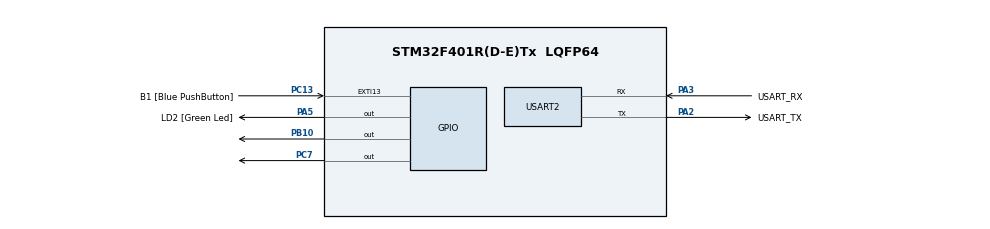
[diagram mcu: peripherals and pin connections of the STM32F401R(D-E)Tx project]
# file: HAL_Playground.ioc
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Mcu.Family=STM32F4
Mcu.Name=STM32F401R(D-E)Tx
Mcu.Package=LQFP64
NVIC.PriorityGroup=NVIC_PRIORITYGROUP_0
PA13.GPIO_Label=TMS
PA13.Mode=Serial_Wire
PA13.Signal=SYS_JTMS-SWDIO
PA14.GPIO_Label=TCK
PA14.Mode=Serial_Wire
PA14.Signal=SYS_JTCK-SWCLK
PA2.GPIO_Label=USART_TX
PA2.GPIO_Mode=GPIO_MODE_AF_PP
PA2.GPIO_PuPd=GPIO_NOPULL
PA2.GPIO_Speed=GPIO_SPEED_FREQ_LOW
PA2.Mode=Asynchronous
PA2.Signal=USART2_TX
PA3.GPIO_Label=USART_RX
PA3.GPIO_Mode=GPIO_MODE_AF_PP
PA3.GPIO_PuPd=GPIO_NOPULL
PA3.GPIO_Speed=GPIO_SPEED_FREQ_LOW
PA3.Mode=Asynchronous
PA3.Signal=USART2_RX
PA5.GPIO_Label=LD2 [Green Led]
PA5.GPIO_Mode=GPIO_MODE_OUTPUT_PP
PA5.GPIO_PuPd=GPIO_NOPULL
PA5.GPIO_Speed=GPIO_SPEED_FREQ_LOW
PA5.Signal=GPIO_Output
PB10.Signal=GPIO_Output
PB3.GPIO_Label=SWO
PB3.Signal=SYS_JTDO-SWO
PC13-ANTI_TAMP.GPIO_Label=B1 [Blue PushButton]
PC13-ANTI_TAMP.GPIO_ModeDefaultEXTI=GPIO_MODE_IT_FALLING
PC13-ANTI_TAMP.GPIO_PuPd=GPIO_NOPULL
PC13-ANTI_TAMP.Signal=GPXTI13
PC14-OSC32_IN.Mode=LSE-External-Oscillator
PC14-OSC32_IN.Signal=RCC_OSC32_IN
PC15-OSC32_OUT.Mode=LSE-External-Oscillator
PC15-OSC32_OUT.Signal=RCC_OSC32_OUT
PC7.Signal=GPIO_Output
PH0\ -\ OSC_IN.Mode=HSE-External-Clock-Source
PH0\ -\ OSC_IN.Signal=RCC_OSC_IN
PH1\ -\ OSC_OUT.Mode=HSE-External-Clock-Source
PH1\ -\ OSC_OUT.Signal=RCC_OSC_OUT
ProjectManager.HeapSize=0x200
ProjectManager.StackSize=0x400
ProjectManager.TargetToolchain=STM32CubeIDE
RCC.48MHZClocksFreq_Value=57142857.14285714
RCC.AHBFreq_Value=16000000
RCC.APB1CLKDivider=RCC_HCLK_DIV2
RCC.APB1Freq_Value=8000000
RCC.APB1TimFreq_Value=16000000
RCC.APB2CLKDivider=RCC_HCLK_DIV2
RCC.APB2Freq_Value=8000000
RCC.APB2TimFreq_Value=16000000
RCC.CortexFreq_Value=16000000
RCC.HCLKFreq_Value=16000000
RCC.HSE_VALUE=8000000
RCC.HSI_VALUE=16000000
RCC.PLLN=400
RCC.PLLP=RCC_PLLP_DIV8
RCC.PLLQ=7
RCC.SYSCLKFreq_VALUE=16000000
RCC.VCOOutputFreq_Value=400000000
TIM1.Period=0xffff-1
TIM1.Prescaler=84-1
USART2.VirtualMode=VM_ASYNC
VP_TIM1_VS_ClockSourceINT.Mode=Internal
board=NUCLEO-F401RE

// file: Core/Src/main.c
/* USER CODE BEGIN Header */
/**
  ******************************************************************************
  * @file           : main.c
  * @brief          : Main program body
  ******************************************************************************
  * @attention
  *
  * Copyright (c) 2024 STMicroelectronics.
  * All rights reserved.
  *
  * This software is licensed under terms that can be found in the LICENSE file
  * in the root directory of this software component.
  * If no LICENSE file comes with this software, it is provided AS-IS.
  *
  ******************************************************************************
  */
/* USER CODE END Header */
#include "main.h"

TIM_HandleTypeDef htim1;

UART_HandleTypeDef huart2;

void SystemClock_Config(void);
static void MX_GPIO_Init(void);
static void MX_USART2_UART_Init(void);
static void MX_TIM1_Init(void);
void delay_us(uint16_t us);

int main(void)
{

  /* MCU Configuration--------------------------------------------------------*/

  /* Reset of all peripherals, Initializes the Flash interface and the Systick. */
  HAL_Init();

  /* Configure the system clock */
  SystemClock_Config();

  /* Initialize all configured peripherals */
  MX_GPIO_Init();
  MX_USART2_UART_Init();
  MX_TIM1_Init();
  HAL_TIM_Base_Start(&htim1);

  /* Infinite loop */
  /* USER CODE BEGIN WHILE */

  //HAL_GPIO_WritePin(GPIOB, GPIO_PIN_4, GPIO_PIN_RESET);
  while (1)
  {
    /* USER CODE END WHILE */
	  /*Configure GPIO pin Output Level */
	   HAL_GPIO_TogglePin(LD2_GPIO_Port, LD2_Pin);
	   HAL_GPIO_TogglePin(GPIOC, GPIO_PIN_7);//D9
	   delay_us(30);

	   HAL_GPIO_TogglePin(LD2_GPIO_Port, LD2_Pin);
	   HAL_GPIO_TogglePin(GPIOC, GPIO_PIN_7);//D9

	   delay_us(6);

  }
}

void SystemClock_Config(void)
{
  RCC_OscInitTypeDef RCC_OscInitStruct = {0};
  RCC_ClkInitTypeDef RCC_ClkInitStruct = {0};

  /** Configure the main internal regulator output voltage
  */
  __HAL_RCC_PWR_CLK_ENABLE();
  __HAL_PWR_VOLTAGESCALING_CONFIG(PWR_REGULATOR_VOLTAGE_SCALE2);

  /** Initializes the RCC Oscillators according to the specified parameters
  * in the RCC_OscInitTypeDef structure.
  */
  RCC_OscInitStruct.OscillatorType = RCC_OSCILLATORTYPE_HSI;
  RCC_OscInitStruct.HSIState = RCC_HSI_ON;
  RCC_OscInitStruct.HSICalibrationValue = RCC_HSICALIBRATION_DEFAULT;
  RCC_OscInitStruct.PLL.PLLState = RCC_PLL_ON;
  RCC_OscInitStruct.PLL.PLLSource = RCC_PLLSOURCE_HSI;
  RCC_OscInitStruct.PLL.PLLM = 16;
  RCC_OscInitStruct.PLL.PLLN = 336;
  RCC_OscInitStruct.PLL.PLLP = RCC_PLLP_DIV4;
  RCC_OscInitStruct.PLL.PLLQ = 7;
  if (HAL_RCC_OscConfig(&RCC_OscInitStruct) != HAL_OK)
  {
    Error_Handler();
  }

  /** Initializes the CPU, AHB and APB buses clocks
  */
  RCC_ClkInitStruct.ClockType = RCC_CLOCKTYPE_HCLK|RCC_CLOCKTYPE_SYSCLK
                              |RCC_CLOCKTYPE_PCLK1|RCC_CLOCKTYPE_PCLK2;
  RCC_ClkInitStruct.SYSCLKSource = RCC_SYSCLKSOURCE_PLLCLK;
  RCC_ClkInitStruct.AHBCLKDivider = RCC_SYSCLK_DIV1;
  RCC_ClkInitStruct.APB1CLKDivider = RCC_HCLK_DIV2;
  RCC_ClkInitStruct.APB2CLKDivider = RCC_HCLK_DIV1;

  if (HAL_RCC_ClockConfig(&RCC_ClkInitStruct, FLASH_LATENCY_2) != HAL_OK)
  {
    Error_Handler();
  }
}

static void MX_TIM1_Init(void)
{

  TIM_ClockConfigTypeDef sClockSourceConfig = {0};
  TIM_MasterConfigTypeDef sMasterConfig = {0};

  htim1.Instance = TIM1;
  htim1.Init.Prescaler = 84-1;
  htim1.Init.CounterMode = TIM_COUNTERMODE_UP;
  htim1.Init.Period = 0xffff-1;
  htim1.Init.ClockDivision = TIM_CLOCKDIVISION_DIV1;
  htim1.Init.RepetitionCounter = 0;
  htim1.Init.AutoReloadPreload = TIM_AUTORELOAD_PRELOAD_DISABLE;
  if (HAL_TIM_Base_Init(&htim1) != HAL_OK)
  {
    Error_Handler();
  }
  sClockSourceConfig.ClockSource = TIM_CLOCKSOURCE_INTERNAL;
  if (HAL_TIM_ConfigClockSource(&htim1, &sClockSourceConfig) != HAL_OK)
  {
    Error_Handler();
  }
  sMasterConfig.MasterOutputTrigger = TIM_TRGO_RESET;
  sMasterConfig.MasterSlaveMode = TIM_MASTERSLAVEMODE_DISABLE;
  if (HAL_TIMEx_MasterConfigSynchronization(&htim1, &sMasterConfig) != HAL_OK)
  {
    Error_Handler();
  }

}

static void MX_USART2_UART_Init(void)
{

  huart2.Instance = USART2;
  huart2.Init.BaudRate = 115200;
  huart2.Init.WordLength = UART_WORDLENGTH_8B;
  huart2.Init.StopBits = UART_STOPBITS_1;
  huart2.Init.Parity = UART_PARITY_NONE;
  huart2.Init.Mode = UART_MODE_TX_RX;
  huart2.Init.HwFlowCtl = UART_HWCONTROL_NONE;
  huart2.Init.OverSampling = UART_OVERSAMPLING_16;
  if (HAL_UART_Init(&huart2) != HAL_OK)
  {
    Error_Handler();
  }

}

static void MX_GPIO_Init(void)
{
  GPIO_InitTypeDef GPIO_InitStruct = {0};

  /* GPIO Ports Clock Enable */
  __HAL_RCC_GPIOC_CLK_ENABLE();
  __HAL_RCC_GPIOH_CLK_ENABLE();
  __HAL_RCC_GPIOA_CLK_ENABLE();
  __HAL_RCC_GPIOB_CLK_ENABLE();

  /*Configure GPIO pin Output Level */
  HAL_GPIO_WritePin(LD2_GPIO_Port, LD2_Pin, GPIO_PIN_RESET);

  /*Configure GPIO pin Output Level */
  HAL_GPIO_WritePin(GPIOB, GPIO_PIN_10, GPIO_PIN_RESET);//D6

  /*Configure GPIO pin Output Level */
  HAL_GPIO_WritePin(GPIOC, GPIO_PIN_7, GPIO_PIN_RESET);//D9

  /*Configure GPIO pin : B1_Pin */
  GPIO_InitStruct.Pin = B1_Pin;
  GPIO_InitStruct.Mode = GPIO_MODE_IT_FALLING;
  GPIO_InitStruct.Pull = GPIO_NOPULL;
  HAL_GPIO_Init(B1_GPIO_Port, &GPIO_InitStruct);

  /*Configure GPIO pin : LD2_Pin */
  GPIO_InitStruct.Pin = LD2_Pin;
  GPIO_InitStruct.Mode = GPIO_MODE_OUTPUT_PP;
  GPIO_InitStruct.Pull = GPIO_NOPULL;
  GPIO_InitStruct.Speed = GPIO_SPEED_FREQ_LOW;
  HAL_GPIO_Init(LD2_GPIO_Port, &GPIO_InitStruct);

  /*Configure GPIO pin : PB10 */
  GPIO_InitStruct.Pin = GPIO_PIN_10;
  GPIO_InitStruct.Mode = GPIO_MODE_OUTPUT_PP;
  GPIO_InitStruct.Pull = GPIO_NOPULL;
  GPIO_InitStruct.Speed = GPIO_SPEED_FREQ_HIGH;
  HAL_GPIO_Init(GPIOB, &GPIO_InitStruct);

  /*Configure GPIO pin : PC7 */
  GPIO_InitStruct.Pin = GPIO_PIN_7;
  GPIO_InitStruct.Mode = GPIO_MODE_OUTPUT_PP;
  GPIO_InitStruct.Pull = GPIO_NOPULL;
  GPIO_InitStruct.Speed = GPIO_SPEED_FREQ_HIGH;
  HAL_GPIO_Init(GPIOC, &GPIO_InitStruct);

}

/* USER CODE BEGIN 4 */

void delay_us(uint16_t us)
{
    // Ensure the timer is started before using this function
    __HAL_TIM_SET_COUNTER(&htim1, 0);  // Reset counter value to 0
    while (__HAL_TIM_GET_COUNTER(&htim1) < us) {
        // Wait for the counter to reach the desired delay
    }
}

/* USER CODE END 4 */

void Error_Handler(void)
{
  __disable_irq();
  while (1)
  {
  }
}
